VERSION 5.7 ;
  NOWIREEXTENSIONATPIN ON ;
  DIVIDERCHAR "/" ;
  BUSBITCHARS "[]" ;
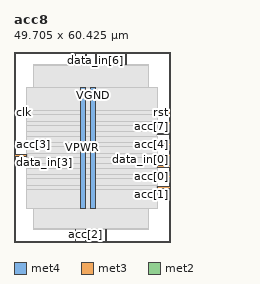
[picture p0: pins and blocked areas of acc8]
MACRO acc8
  CLASS BLOCK ;
  FOREIGN acc8 ;
  ORIGIN 0.000 0.000 ;
  SIZE 49.705 BY 60.425 ;
  PIN VGND
    DIRECTION INOUT ;
    USE GROUND ;
    PORT
      LAYER met4 ;
        RECT 24.340 10.640 25.940 49.200 ;
    END
  END VGND
  PIN VPWR
    DIRECTION INOUT ;
    USE POWER ;
    PORT
      LAYER met4 ;
        RECT 21.040 10.640 22.640 49.200 ;
    END
  END VPWR
  PIN acc[0]
    DIRECTION OUTPUT ;
    USE SIGNAL ;
    ANTENNADIFFAREA 0.445500 ;
    PORT
      LAYER met3 ;
        RECT 45.705 20.440 49.705 21.040 ;
    END
  END acc[0]
  PIN acc[1]
    DIRECTION OUTPUT ;
    USE SIGNAL ;
    ANTENNADIFFAREA 0.445500 ;
    PORT
      LAYER met3 ;
        RECT 45.705 17.040 49.705 17.640 ;
    END
  END acc[1]
  PIN acc[2]
    DIRECTION OUTPUT ;
    USE SIGNAL ;
    ANTENNADIFFAREA 0.445500 ;
    PORT
      LAYER met2 ;
        RECT 22.630 0.000 22.910 4.000 ;
    END
  END acc[2]
  PIN acc[3]
    DIRECTION OUTPUT ;
    USE SIGNAL ;
    ANTENNADIFFAREA 0.445500 ;
    PORT
      LAYER met3 ;
        RECT 0.000 30.640 4.000 31.240 ;
    END
  END acc[3]
  PIN acc[4]
    DIRECTION OUTPUT ;
    USE SIGNAL ;
    ANTENNADIFFAREA 0.445500 ;
    PORT
      LAYER met3 ;
        RECT 45.705 30.640 49.705 31.240 ;
    END
  END acc[4]
  PIN acc[5]
    DIRECTION OUTPUT ;
    USE SIGNAL ;
    ANTENNADIFFAREA 0.445500 ;
    PORT
      LAYER met2 ;
        RECT 19.410 56.425 19.690 60.425 ;
    END
  END acc[5]
  PIN acc[6]
    DIRECTION OUTPUT ;
    USE SIGNAL ;
    ANTENNADIFFAREA 0.445500 ;
    PORT
      LAYER met2 ;
        RECT 35.510 56.425 35.790 60.425 ;
    END
  END acc[6]
  PIN acc[7]
    DIRECTION OUTPUT ;
    USE SIGNAL ;
    ANTENNADIFFAREA 0.445500 ;
    PORT
      LAYER met3 ;
        RECT 45.705 34.040 49.705 34.640 ;
    END
  END acc[7]
  PIN clk
    DIRECTION INPUT ;
    USE SIGNAL ;
    ANTENNAGATEAREA 0.852000 ;
    PORT
      LAYER met3 ;
        RECT 0.000 40.840 4.000 41.440 ;
    END
  END clk
  PIN data_in[0]
    DIRECTION INPUT ;
    USE SIGNAL ;
    ANTENNAGATEAREA 0.196500 ;
    PORT
      LAYER met3 ;
        RECT 45.705 23.840 49.705 24.440 ;
    END
  END data_in[0]
  PIN data_in[1]
    DIRECTION INPUT ;
    USE SIGNAL ;
    ANTENNAGATEAREA 0.196500 ;
    PORT
      LAYER met2 ;
        RECT 29.070 0.000 29.350 4.000 ;
    END
  END data_in[1]
  PIN data_in[2]
    DIRECTION INPUT ;
    USE SIGNAL ;
    ANTENNAGATEAREA 0.196500 ;
    PORT
      LAYER met2 ;
        RECT 19.410 0.000 19.690 4.000 ;
    END
  END data_in[2]
  PIN data_in[3]
    DIRECTION INPUT ;
    USE SIGNAL ;
    ANTENNAGATEAREA 0.196500 ;
    PORT
      LAYER met3 ;
        RECT 0.000 27.240 4.000 27.840 ;
    END
  END data_in[3]
  PIN data_in[4]
    DIRECTION INPUT ;
    USE SIGNAL ;
    ANTENNAGATEAREA 0.196500 ;
    PORT
      LAYER met3 ;
        RECT 45.705 27.240 49.705 27.840 ;
    END
  END data_in[4]
  PIN data_in[5]
    DIRECTION INPUT ;
    USE SIGNAL ;
    ANTENNAGATEAREA 0.196500 ;
    PORT
      LAYER met2 ;
        RECT 22.630 56.425 22.910 60.425 ;
    END
  END data_in[5]
  PIN data_in[6]
    DIRECTION INPUT ;
    USE SIGNAL ;
    ANTENNAGATEAREA 0.196500 ;
    PORT
      LAYER met2 ;
        RECT 25.850 56.425 26.130 60.425 ;
    END
  END data_in[6]
  PIN data_in[7]
    DIRECTION INPUT ;
    USE SIGNAL ;
    ANTENNAGATEAREA 0.196500 ;
    PORT
      LAYER met3 ;
        RECT 45.705 37.440 49.705 38.040 ;
    END
  END data_in[7]
  PIN rst
    DIRECTION INPUT ;
    USE SIGNAL ;
    ANTENNAGATEAREA 0.213000 ;
    PORT
      LAYER met3 ;
        RECT 45.705 40.840 49.705 41.440 ;
    END
  END rst
  OBS
      LAYER nwell ;
        RECT 5.330 10.795 44.350 49.045 ;
      LAYER li1 ;
        RECT 5.520 10.795 44.160 49.045 ;
      LAYER met1 ;
        RECT 5.520 10.640 44.460 49.200 ;
      LAYER met2 ;
        RECT 6.070 56.145 19.130 56.425 ;
        RECT 19.970 56.145 22.350 56.425 ;
        RECT 23.190 56.145 25.570 56.425 ;
        RECT 26.410 56.145 35.230 56.425 ;
        RECT 36.070 56.145 42.690 56.425 ;
        RECT 6.070 4.280 42.690 56.145 ;
        RECT 6.070 4.000 19.130 4.280 ;
        RECT 19.970 4.000 22.350 4.280 ;
        RECT 23.190 4.000 28.790 4.280 ;
        RECT 29.630 4.000 42.690 4.280 ;
      LAYER met3 ;
        RECT 4.000 41.840 45.705 49.125 ;
        RECT 4.400 40.440 45.305 41.840 ;
        RECT 4.000 38.440 45.705 40.440 ;
        RECT 4.000 37.040 45.305 38.440 ;
        RECT 4.000 35.040 45.705 37.040 ;
        RECT 4.000 33.640 45.305 35.040 ;
        RECT 4.000 31.640 45.705 33.640 ;
        RECT 4.400 30.240 45.305 31.640 ;
        RECT 4.000 28.240 45.705 30.240 ;
        RECT 4.400 26.840 45.305 28.240 ;
        RECT 4.000 24.840 45.705 26.840 ;
        RECT 4.000 23.440 45.305 24.840 ;
        RECT 4.000 21.440 45.705 23.440 ;
        RECT 4.000 20.040 45.305 21.440 ;
        RECT 4.000 18.040 45.705 20.040 ;
        RECT 4.000 16.640 45.305 18.040 ;
        RECT 4.000 10.715 45.705 16.640 ;
  END
END acc8
END LIBRARY

